One B-rep face of a CAD part: STEP entity #745.
In plain terms, the planar face has unit normal (0, 0, 1).
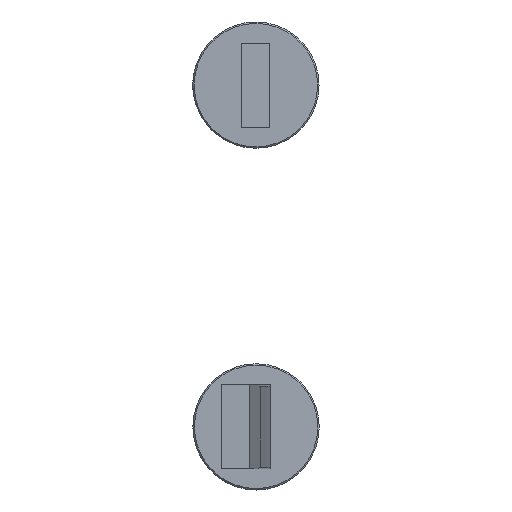
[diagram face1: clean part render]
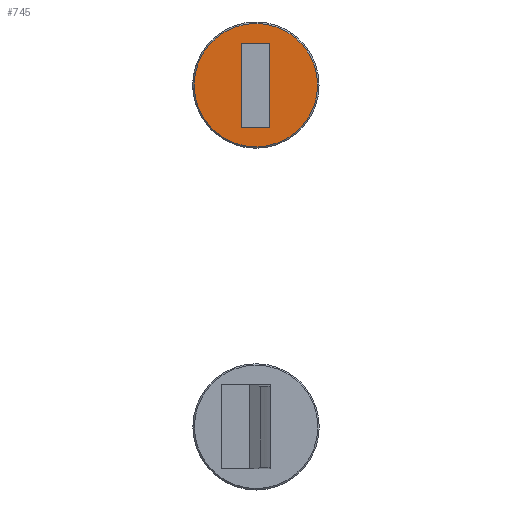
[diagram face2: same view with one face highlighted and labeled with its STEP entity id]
Its self-contained STEP definition (entity closure, numbers rounded to 3 decimals):
#23 = CIRCLE ( 'NONE', #24, 8.8 ) ;
#24 = AXIS2_PLACEMENT_3D ( 'NONE', #967, #969, #963 ) ;
#62 = AXIS2_PLACEMENT_3D ( 'NONE', #1215, #1240, #1216 ) ;
#104 = VERTEX_POINT ( 'NONE', #454 ) ;
#112 = VERTEX_POINT ( 'NONE', #456 ) ;
#120 = VERTEX_POINT ( 'NONE', #469 ) ;
#122 = VERTEX_POINT ( 'NONE', #2501 ) ;
#124 = VERTEX_POINT ( 'NONE', #2506 ) ;
#140 = EDGE_LOOP ( 'NONE', ( #403, #392, #364, #407 ) ) ;
#157 = EDGE_LOOP ( 'NONE', ( #368, #377 ) ) ;
#227 = VERTEX_POINT ( 'NONE', #2509 ) ;
#364 = ORIENTED_EDGE ( 'NONE', *, *, #902, .T. ) ;
#368 = ORIENTED_EDGE ( 'NONE', *, *, #818, .F. ) ;
#377 = ORIENTED_EDGE ( 'NONE', *, *, #777, .F. ) ;
#392 = ORIENTED_EDGE ( 'NONE', *, *, #925, .T. ) ;
#403 = ORIENTED_EDGE ( 'NONE', *, *, #822, .T. ) ;
#407 = ORIENTED_EDGE ( 'NONE', *, *, #794, .T. ) ;
#454 = CARTESIAN_POINT ( 'NONE',  ( -6., 2., 8. ) ) ;
#456 = CARTESIAN_POINT ( 'NONE',  ( 0., 8.8, 8. ) ) ;
#469 = CARTESIAN_POINT ( 'NONE',  ( -6., -2., 8. ) ) ;
#719 = VECTOR ( 'NONE', #1106, 1000. ) ;
#745 = ADVANCED_FACE ( 'NONE', ( #1217, #1243 ), #1222, .T. ) ;
#777 = EDGE_CURVE ( 'NONE', #124, #112, #23, .T. ) ;
#794 = EDGE_CURVE ( 'NONE', #120, #104, #1131, .T. ) ;
#818 = EDGE_CURVE ( 'NONE', #112, #124, #2215, .T. ) ;
#822 = EDGE_CURVE ( 'NONE', #104, #227, #2108, .T. ) ;
#902 = EDGE_CURVE ( 'NONE', #122, #120, #1653, .T. ) ;
#925 = EDGE_CURVE ( 'NONE', #227, #122, #1725, .T. ) ;
#963 = DIRECTION ( 'NONE',  ( 0., 1., 0. ) ) ;
#967 = CARTESIAN_POINT ( 'NONE',  ( 0., 0., 8. ) ) ;
#969 = DIRECTION ( 'NONE',  ( 0., 0., -1. ) ) ;
#1106 = DIRECTION ( 'NONE',  ( 0., 1., 0. ) ) ;
#1115 = CARTESIAN_POINT ( 'NONE',  ( -6., 0., 8. ) ) ;
#1131 = LINE ( 'NONE', #1115, #719 ) ;
#1215 = CARTESIAN_POINT ( 'NONE',  ( 0., 0., 8. ) ) ;
#1216 = DIRECTION ( 'NONE',  ( 1., 0., 0. ) ) ;
#1217 = FACE_BOUND ( 'NONE', #140, .T. ) ;
#1222 = PLANE ( 'NONE',  #62 ) ;
#1240 = DIRECTION ( 'NONE',  ( 0., 0., 1. ) ) ;
#1243 = FACE_OUTER_BOUND ( 'NONE', #157, .T. ) ;
#1627 = DIRECTION ( 'NONE',  ( -1., 0., 0. ) ) ;
#1649 = CARTESIAN_POINT ( 'NONE',  ( 0., -2., 8. ) ) ;
#1653 = LINE ( 'NONE', #1649, #2327 ) ;
#1710 = DIRECTION ( 'NONE',  ( 0., -1., 0. ) ) ;
#1716 = CARTESIAN_POINT ( 'NONE',  ( 6., 0., 8. ) ) ;
#1725 = LINE ( 'NONE', #1716, #2398 ) ;
#2074 = DIRECTION ( 'NONE',  ( 0., 0., -1. ) ) ;
#2086 = CARTESIAN_POINT ( 'NONE',  ( 0., 0., 8. ) ) ;
#2091 = DIRECTION ( 'NONE',  ( 0., 1., 0. ) ) ;
#2108 = LINE ( 'NONE', #2111, #2219 ) ;
#2111 = CARTESIAN_POINT ( 'NONE',  ( 0., 2., 8. ) ) ;
#2142 = DIRECTION ( 'NONE',  ( 1., 0., 0. ) ) ;
#2199 = AXIS2_PLACEMENT_3D ( 'NONE', #2086, #2074, #2091 ) ;
#2215 = CIRCLE ( 'NONE', #2199, 8.8 ) ;
#2219 = VECTOR ( 'NONE', #2142, 1000. ) ;
#2327 = VECTOR ( 'NONE', #1627, 1000. ) ;
#2398 = VECTOR ( 'NONE', #1710, 1000. ) ;
#2501 = CARTESIAN_POINT ( 'NONE',  ( 6., -2., 8. ) ) ;
#2506 = CARTESIAN_POINT ( 'NONE',  ( 0., -8.8, 8. ) ) ;
#2509 = CARTESIAN_POINT ( 'NONE',  ( 6., 2., 8. ) ) ;
